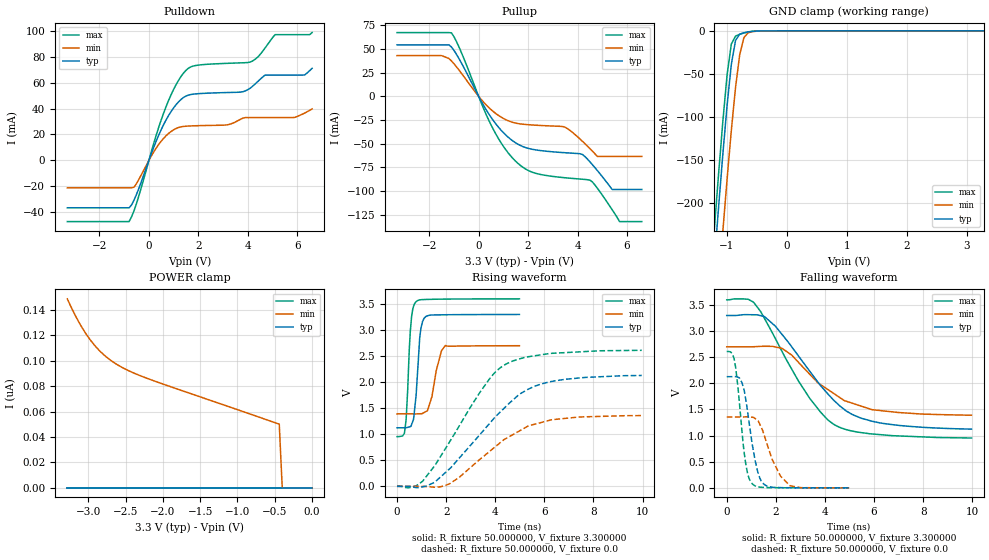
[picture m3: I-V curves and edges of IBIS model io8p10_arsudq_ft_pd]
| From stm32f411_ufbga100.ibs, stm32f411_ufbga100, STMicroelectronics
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|   Model io8p10_arsudq_ft_pd
[Model]  io8p10_arsudq_ft_pd
Model_type I/O
Polarity   Non-Inverting
Enable   Active-Low
Vinl =   0.990000V
Vinh =   2.310000V
Vmeas =  1.650000V
Cref =   40.000000pF
Rref =   100.000000M
Vref =   0.0V
C_comp   2.292100pF   2.228000pF   2.366600pF
[Temperature Range]   25.000000   0.125000k   -40.000000
[Pullup Reference]   3.300000V   2.700000V   3.600000V
[Pulldown Reference]   0.0V   0.0V   0.0V
[POWER Clamp Reference]   3.300000V   2.700000V   3.600000V
[GND Clamp Reference]   0.0V   0.0V   0.0V
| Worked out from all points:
|   slope of the pulldown table from 0 to 0.495 V, typ, clamps not added: 20.9 ohm
|   slope of the pullup table from 0 to 0.495 V, typ, clamps not added: 22.6 ohm
|   GND clamp passes 1 mA (typ) near -0.62 V on its own axis
|   rising waveform, R_fixture 50.000000, V_fixture 3.300000: 20-80 % time 194ps typ, 344ps min, 164ps max; typ from 1.12 V to 3.3 V
|   rising waveform, R_fixture 50.000000, V_fixture 0.0: 20-80 % time 2.51ns typ, 2.3ns min, 2.11ns max; typ from 0 V to 2.13 V
|   falling waveform, R_fixture 50.000000, V_fixture 3.300000: 20-80 % time 2.25ns typ, 2.05ns min, 2.03ns max; typ from 3.3 V to 1.12 V
|   falling waveform, R_fixture 50.000000, V_fixture 0.0: 20-80 % time 433ps typ, 668ps min, 339ps max; typ from 2.13 V to 0 V
[Pulldown]
|Voltage   I(typ)   I(min)   I(max)
-3.3V     -36.46mA   -21.1mA    -47.09mA
-800mV    -36.46mA   -21.1mA    -47.09mA
-600mV    -30.5mA    -20.54mA   -38.69mA
700mV     31.4mA     19.11mA    41.71mA
1.2V      45.15mA    25.37mA    61.75mA
1.6V      50.35mA    26.5mA     71.06mA
3.1V      52.27mA    27.26mA    74.75mA
4.1V      55.7mA     32.99mA    75.8mA
4.7V      65.72mA    32.99mA    86.69mA
5.1V      65.72mA    32.99mA    96.9mA
6.3V      65.87mA    36.5mA     96.9mA
6.6V      70.93mA    39.71mA    98.5mA
[Pullup]
|Voltage   I(typ)   I(min)   I(max)
-3.3V     54.22mA    42.91mA    67.18mA
-1.1V     51.99mA    37.29mA    66.9mA
500mV     -22.07mA   -14mA      -30.03mA
1.5V      -49.1mA    -28.3mA    -68.56mA
2.2V      -56.04mA   -30.32mA   -80.35mA
3.5V      -59.53mA   -32.65mA   -85.92mA
4.2V      -61.43mA   -47.49mA   -87.46mA
4.5V      -69.06mA   -55.13mA   -88.38mA
4.8V      -78.22mA   -63.4mA    -96.84mA
5.4V      -98.3mA    -63.4mA    -119.6mA
5.7V      -98.3mA    -63.4mA    -132.1mA
6.6V      -98.3mA    -63.4mA    -132.1mA
[GND_clamp]
|Voltage   I(typ)   I(min)   I(max)
-3.3V     -2.316A    -2.396A    -2.289A
-1.2V     -265.5mA   -356.1mA   -227.2mA
-1.13V    -202.7mA   -292.9mA   -164.1mA
-1.06V    -142.2mA   -231.2mA   -104.1mA
-990mV    -85.98mA   -171.6mA   -50.73mA
-920mV    -38.81mA   -115.5mA   -15.29mA
-850mV    -11.09mA   -65.61mA   -6.016mA
-780mV    -3.793mA   -27.42mA   -3.89mA
-710mV    -2.098mA   -7.698mA   -2.396mA
-640mV    -1.159mA   -2.127mA   -1.234mA
-570mV    -535.1uA   -807.4uA   -490.2uA
3.28V     81.28uA    57.87uA    93.98uA
[POWER_clamp]
|Voltage   I(typ)   I(min)   I(max)
-3.28V    0A         148.5nA    0A
-3.2V     0A         138.6nA    0A
-3.12V    0A         129.7nA    0A
-3.04V    0A         122nA      0A
-2.96V    0A         115.3nA    0A
-2.8V     0A         105.1nA    0A
-2.6V     0A         96.44nA    0A
-2.4V     0A         90.52nA    0A
-2.16V    0A         84.97nA    0A
-440mV    0A         50.04nA    0A
-400mV    0A         0A         0A
0V        0A         0A         0A
[Ramp]
| variable   typ   min   max
dV/dt_r  1.26672/2.50881n   0.81108/2.29846n   1.56456/2.11400n
dV/dt_f  1.28292/2.24001n   0.77724/2.03584n   1.57467/2.02797n
R_load = 50.000000
[Rising Waveform]
R_fixture= 50.000000
V_fixture= 3.300000
V_fixture_min= 2.700000
V_fixture_max= 3.600000
|time   V(typ)   V(min)   V(max)
0s        1.123V     1.391V     953.9mV
300.3ps   1.125V     1.391V     1.016V
370.4ps   1.127V     1.391V     1.28V
550.6ps   1.148V     1.391V     3.028V
670.7ps   1.282V     1.39V      3.45V
760.8ps   1.673V     1.39V      3.536V
940.9ps   2.92V      1.393V     3.579V
1.171ns   3.258V     1.433V     3.586V
1.962ns   3.293V     2.701V     3.593V
4.985ns   3.299V     2.699V     3.598V
[Rising Waveform]
R_fixture= 50.000000
V_fixture= 0.0
V_fixture_min= 0.0
V_fixture_max= 0.0
|time   V(typ)   V(min)   V(max)
0s        344.7uV    197.4uV    679.1uV
460.5ps   -2.486mV   133.5uV    -29.07mV
1.041ns   -10.16mV   -1.939mV   97.44mV
1.542ns   82.09mV    -17.48mV   399.5mV
2.162ns   344.6mV    55.61mV    869.5mV
3.744ns   1.193V     660.3mV    2.047V
4.444ns   1.537V     919.7mV    2.347V
5.285ns   1.85V      1.143V     2.482V
6.186ns   2.002V     1.264V     2.547V
9.97ns    2.127V     1.357V     2.611V
[Falling Waveform]
R_fixture= 50.000000
V_fixture= 3.300000
V_fixture_min= 2.700000
V_fixture_max= 3.600000
|time   V(typ)   V(min)   V(max)
0s        3.299V     2.699V     3.598V
880.9ps   3.314V     2.699V     3.608V
1.101ns   3.312V     2.701V     3.547V
1.542ns   3.275V     2.709V     3.238V
2.242ns   2.942V     2.672V     2.62V
3.383ns   2.231V     2.173V     1.711V
4.384ns   1.665V     1.798V     1.208V
5.125ns   1.402V     1.618V     1.085V
6.206ns   1.246V     1.482V     1.02V
9.97ns    1.123V     1.391V     953.9mV
[Falling Waveform]
R_fixture= 50.000000
V_fixture= 0.0
V_fixture_min= 0.0
V_fixture_max= 0.0
|time   V(typ)   V(min)   V(max)
0s        2.127V     1.357V     2.611V
300.3ps   2.129V     1.357V     2.473V
450.5ps   2.118V     1.357V     1.954V
620.6ps   2.014V     1.357V     1.08V
840.8ps   1.488V     1.359V     294.2mV
1.041ns   828.7mV    1.351V     77.84mV
1.451ns   100.8mV    1.113V     9.809mV
1.852ns   12.96mV    542.8mV    3.743mV
2.583ns   2.093mV    38.53mV    1.697mV
4.985ns   344.7uV    197.4uV    679.1uV
